VERSION 5.8 ;
BUSBITCHARS "[]" ;
DIVIDERCHAR "/" ;
UNITS
    DATABASE MICRONS 1000 ;
END UNITS

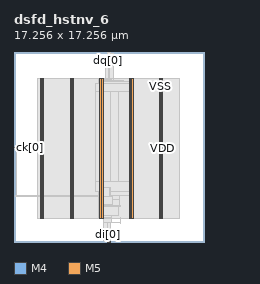
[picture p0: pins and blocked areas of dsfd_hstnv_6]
MACRO dsfd_hstnv_6
  FOREIGN dsfd_hstnv_6 0 0 ;
  CLASS BLOCK ;
  SIZE 17.256 BY 17.256 ;
  PIN ck[0]
    DIRECTION INPUT ;
    USE SIGNAL ;
    PORT
      LAYER M4 ;
        RECT  0 8.592 0.084 8.616 ;
    END
    PORT
      LAYER M4 ;
        RECT  0.06 8.592 0.227 8.616 ;
    END
  END ck[0]
  PIN di[0]
    DIRECTION INPUT ;
    USE SIGNAL ;
    PORT
      LAYER M5 ;
        RECT  8.496 0 8.52 0.084 ;
    END
  END di[0]
  PIN di[1]
    DIRECTION INPUT ;
    USE SIGNAL ;
    PORT
      LAYER M5 ;
        RECT  8.544 0 8.568 0.084 ;
    END
  END di[1]
  PIN di[2]
    DIRECTION INPUT ;
    USE SIGNAL ;
    PORT
      LAYER M5 ;
        RECT  8.592 0 8.616 0.084 ;
    END
  END di[2]
  PIN di[3]
    DIRECTION INPUT ;
    USE SIGNAL ;
    PORT
      LAYER M5 ;
        RECT  8.64 0 8.664 0.084 ;
    END
  END di[3]
  PIN di[4]
    DIRECTION INPUT ;
    USE SIGNAL ;
    PORT
      LAYER M5 ;
        RECT  8.688 0 8.712 0.084 ;
    END
  END di[4]
  PIN di[5]
    DIRECTION INPUT ;
    USE SIGNAL ;
    PORT
      LAYER M5 ;
        RECT  8.736 0 8.76 0.084 ;
    END
  END di[5]
  PIN dq[0]
    DIRECTION OUTPUT ;
    USE SIGNAL ;
    PORT
      LAYER M5 ;
        RECT  8.496 17.172 8.52 17.256 ;
    END
  END dq[0]
  PIN dq[1]
    DIRECTION OUTPUT ;
    USE SIGNAL ;
    PORT
      LAYER M5 ;
        RECT  8.544 17.172 8.568 17.256 ;
    END
  END dq[1]
  PIN dq[2]
    DIRECTION OUTPUT ;
    USE SIGNAL ;
    PORT
      LAYER M5 ;
        RECT  8.592 17.172 8.616 17.256 ;
    END
  END dq[2]
  PIN dq[3]
    DIRECTION OUTPUT ;
    USE SIGNAL ;
    PORT
      LAYER M5 ;
        RECT  8.64 17.172 8.664 17.256 ;
    END
  END dq[3]
  PIN dq[4]
    DIRECTION OUTPUT ;
    USE SIGNAL ;
    PORT
      LAYER M5 ;
        RECT  8.688 17.172 8.712 17.256 ;
    END
  END dq[4]
  PIN dq[5]
    DIRECTION OUTPUT ;
    USE SIGNAL ;
    PORT
      LAYER M5 ;
        RECT  8.736 17.172 8.76 17.256 ;
    END
  END dq[5]
  PIN VDD
    DIRECTION INOUT ;
    USE POWER ;
    PORT
      LAYER M5 ;
        RECT  13.392 2.151 13.512 14.873 ;
        RECT  10.692 2.151 10.812 14.873 ;
        RECT  7.992 2.151 8.112 14.873 ;
        RECT  5.292 2.151 5.412 14.873 ;
        RECT  2.592 2.151 2.712 14.873 ;
    END
  END VDD
  PIN VSS
    DIRECTION INOUT ;
    USE GROUND ;
    PORT
      LAYER M5 ;
        RECT  13.2 2.137 13.32 14.859 ;
        RECT  10.5 2.137 10.62 14.859 ;
        RECT  7.8 2.137 7.92 14.859 ;
        RECT  5.1 2.137 5.22 14.859 ;
        RECT  2.4 2.137 2.52 14.859 ;
    END
  END VSS
  # OT_OBS_CLOSED layer=M5 d_um=1.536 added=1
  OBS
    LAYER RVTN ;
     RECT  2.16 2.16 15.066 2.295 ;
     RECT  2.16 2.565 15.066 2.835 ;
     RECT  2.16 3.105 15.066 3.375 ;
     RECT  2.16 3.645 15.066 3.915 ;
     RECT  2.16 4.185 15.066 4.455 ;
     RECT  2.16 4.725 15.066 4.995 ;
     RECT  2.16 5.265 15.066 5.535 ;
     RECT  2.16 5.805 15.066 6.075 ;
     RECT  2.16 6.345 15.066 6.615 ;
     RECT  2.16 6.885 15.066 7.155 ;
     RECT  2.16 7.425 15.066 7.695 ;
     RECT  2.16 7.965 15.066 8.235 ;
     RECT  2.16 8.505 15.066 8.775 ;
     RECT  2.16 9.045 15.066 9.315 ;
     RECT  2.16 9.585 15.066 9.855 ;
     RECT  2.16 10.125 15.066 10.395 ;
     RECT  2.16 10.665 15.066 10.935 ;
     RECT  2.16 11.205 15.066 11.475 ;
     RECT  2.16 11.745 15.066 12.015 ;
     RECT  2.16 12.285 15.066 12.555 ;
     RECT  2.16 12.825 15.066 13.095 ;
     RECT  2.16 13.365 15.066 13.635 ;
     RECT  2.16 13.905 15.066 14.175 ;
     RECT  2.16 14.445 15.066 14.715 ;
    LAYER RVTP ;
     RECT  2.16 2.295 15.066 2.565 ;
     RECT  2.16 2.835 15.066 3.105 ;
     RECT  2.16 3.375 15.066 3.645 ;
     RECT  2.16 3.915 15.066 4.185 ;
     RECT  2.16 4.455 15.066 4.725 ;
     RECT  2.16 4.995 15.066 5.265 ;
     RECT  2.16 5.535 15.066 5.805 ;
     RECT  2.16 6.075 15.066 6.345 ;
     RECT  2.16 6.615 15.066 6.885 ;
     RECT  2.16 7.155 15.066 7.425 ;
     RECT  2.16 7.695 15.066 7.965 ;
     RECT  2.16 8.235 15.066 8.505 ;
     RECT  2.16 8.775 15.066 9.045 ;
     RECT  2.16 9.315 15.066 9.585 ;
     RECT  2.16 9.855 15.066 10.125 ;
     RECT  2.16 10.395 15.066 10.665 ;
     RECT  2.16 10.935 15.066 11.205 ;
     RECT  2.16 11.475 15.066 11.745 ;
     RECT  2.16 12.015 15.066 12.285 ;
     RECT  2.16 12.555 15.066 12.825 ;
     RECT  2.16 13.095 15.066 13.365 ;
     RECT  2.16 13.635 15.066 13.905 ;
     RECT  2.16 14.175 15.066 14.445 ;
     RECT  2.16 14.715 15.066 14.85 ;
    LAYER M1 ;
     RECT  2.16 2.151 15.066 14.859 ;
    LAYER M2 ;
     RECT  2.16 2.151 7.699 14.859 ;
     RECT  7.699 2.106 8.591 14.859 ;
     RECT  8.591 2.151 15.066 14.859 ;
    LAYER M3 ;
     RECT  8.136 0.139 8.154 0.187 ;
     RECT  8.136 0.187 8.514 0.571 ;
     RECT  8.136 0.571 8.586 1.771 ;
     RECT  8.136 1.771 8.838 2.101 ;
     RECT  7.704 2.101 8.838 2.219 ;
     RECT  9.684 1.723 9.702 2.255 ;
     RECT  7.815 2.219 8.838 2.371 ;
     RECT  2.415 2.143 2.505 2.413 ;
     RECT  5.115 2.143 5.205 2.413 ;
     RECT  10.515 2.143 10.605 2.413 ;
     RECT  13.215 2.143 13.305 2.413 ;
     RECT  7.815 2.371 9.45 3.181 ;
     RECT  7.815 3.181 9.666 3.299 ;
     RECT  7.815 3.299 9.558 3.847 ;
     RECT  7.704 3.847 9.558 4.261 ;
     RECT  10.515 2.413 10.797 4.261 ;
     RECT  7.704 4.261 10.797 4.621 ;
     RECT  7.416 4.621 10.797 5.459 ;
     RECT  7.416 5.459 8.766 13.711 ;
     RECT  9.504 5.459 10.797 13.711 ;
     RECT  7.416 13.711 10.797 14.369 ;
     RECT  2.415 2.413 2.697 14.597 ;
     RECT  5.115 2.413 5.397 14.597 ;
     RECT  7.704 14.369 10.797 14.597 ;
     RECT  13.215 2.413 13.497 14.597 ;
     RECT  7.704 14.597 9.918 14.639 ;
     RECT  8.007 14.639 9.702 14.675 ;
     RECT  2.607 14.597 2.697 14.867 ;
     RECT  5.307 14.597 5.397 14.867 ;
     RECT  8.007 14.675 9.018 14.867 ;
     RECT  10.707 14.597 10.797 14.867 ;
     RECT  13.407 14.597 13.497 14.867 ;
     RECT  8.352 14.867 9.018 16.013 ;
     RECT  8.388 16.013 9.018 16.589 ;
     RECT  9 16.589 9.018 17.117 ;
    LAYER M4 ;
     RECT  0.181 4.176 2.408 4.2 ;
     RECT  2.408 2.148 2.512 14.592 ;
     RECT  2.512 2.418 2.6 14.592 ;
     RECT  2.6 2.418 2.704 14.862 ;
     RECT  2.704 4.176 5.108 4.2 ;
     RECT  5.108 2.148 5.212 14.592 ;
     RECT  5.212 2.418 5.3 14.592 ;
     RECT  5.3 2.418 5.404 14.862 ;
     RECT  5.404 4.176 7.693 4.2 ;
     RECT  7.693 3.888 7.808 4.2 ;
     RECT  7.808 2.148 8 14.592 ;
     RECT  8 2.148 8.104 14.862 ;
     RECT  8.341 15.984 8.377 16.008 ;
     RECT  8.125 0.144 8.485 0.168 ;
     RECT  8.377 15.984 8.531 16.584 ;
     RECT  8.104 14.784 8.549 14.862 ;
     RECT  8.531 15.984 8.549 16.008 ;
     RECT  8.485 0.144 8.557 0.216 ;
     RECT  8.557 0.144 8.579 0.6 ;
     RECT  8.549 14.784 8.579 16.008 ;
     RECT  8.579 14.784 8.633 15.96 ;
     RECT  8.579 0.192 8.641 0.6 ;
     RECT  8.641 0.192 8.723 0.216 ;
     RECT  8.104 3.408 8.723 4.92 ;
     RECT  8.633 15.936 8.777 15.96 ;
     RECT  8.633 14.784 8.813 14.808 ;
     RECT  8.477 1.728 8.849 1.8 ;
     RECT  8.723 3.408 8.963 4.104 ;
     RECT  8.629 17.088 9.029 17.112 ;
     RECT  8.849 1.728 9.713 1.752 ;
     RECT  10.508 2.148 10.612 14.592 ;
     RECT  10.612 2.418 10.7 14.592 ;
     RECT  10.7 2.418 10.804 14.862 ;
     RECT  13.208 2.148 13.312 14.592 ;
     RECT  13.312 2.418 13.4 14.592 ;
     RECT  13.4 2.418 13.504 14.862 ;
    LAYER M5 ;
     RECT  8.496 0.016 8.76 1.811 ;
     RECT  2.4 2.137 2.52 2.151 ;
     RECT  5.1 2.137 5.22 2.151 ;
     RECT  10.5 2.137 10.62 2.151 ;
     RECT  13.2 2.137 13.32 2.151 ;
     RECT  7.8 2.137 8.112 3.397 ;
     RECT  7.8 3.397 8.952 4.115 ;
     RECT  7.8 4.115 8.712 4.931 ;
     RECT  0.192 4.165 0.216 8.627 ;
     RECT  7.8 4.931 8.112 14.773 ;
     RECT  2.4 2.151 2.712 14.859 ;
     RECT  5.1 2.151 5.412 14.859 ;
     RECT  7.8 14.773 8.712 14.859 ;
     RECT  10.5 2.151 10.812 14.859 ;
     RECT  13.2 2.151 13.512 14.859 ;
     RECT  2.592 14.859 2.712 14.873 ;
     RECT  5.292 14.859 5.412 14.873 ;
     RECT  7.992 14.859 8.712 14.873 ;
     RECT  10.692 14.859 10.812 14.873 ;
     RECT  13.392 14.859 13.512 14.873 ;
     RECT  8.592 14.873 8.712 15.925 ;
     RECT  8.592 15.925 8.76 15.973 ;
     RECT  8.544 15.973 8.76 16.549 ;
     RECT  8.496 16.549 8.76 17.232 ;
     RECT  8.544 14.873 8.592 15.973 ;
  END
END dsfd_hstnv_6
END LIBRARY
